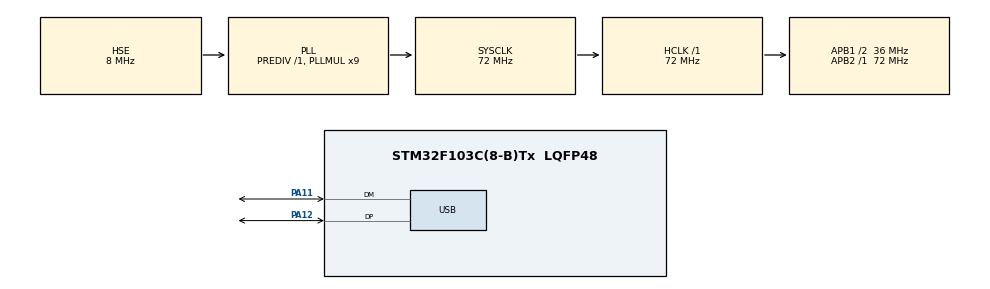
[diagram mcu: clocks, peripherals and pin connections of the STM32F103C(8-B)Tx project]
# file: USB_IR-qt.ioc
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Mcu.Family=STM32F1
Mcu.Name=STM32F103C(8-B)Tx
Mcu.Package=LQFP48
NVIC.PriorityGroup=NVIC_PRIORITYGROUP_4
NVIC.USB_LP_CAN1_RX0_IRQn=true\:0\:0\:false\:false\:true
PA11.Mode=Device
PA11.Signal=USB_DM
PA12.Mode=Device
PA12.Signal=USB_DP
PA13.Mode=Serial_Wire
PA13.Signal=SYS_JTMS-SWDIO
PA14.Mode=Serial_Wire
PA14.Signal=SYS_JTCK-SWCLK
PC14-OSC32_IN.Mode=LSE-External-Oscillator
PC14-OSC32_IN.Signal=RCC_OSC32_IN
PC15-OSC32_OUT.Mode=LSE-External-Oscillator
PC15-OSC32_OUT.Signal=RCC_OSC32_OUT
PD0-OSC_IN.Mode=HSE-External-Oscillator
PD0-OSC_IN.Signal=RCC_OSC_IN
PD1-OSC_OUT.Mode=HSE-External-Oscillator
PD1-OSC_OUT.Signal=RCC_OSC_OUT
ProjectManager.HeapSize=0x200
ProjectManager.StackSize=0x400
ProjectManager.TargetToolchain=Makefile
RCC.AHBFreq_Value=72000000
RCC.APB1CLKDivider=RCC_HCLK_DIV2
RCC.APB1Freq_Value=36000000
RCC.APB1TimFreq_Value=72000000
RCC.APB2Freq_Value=72000000
RCC.APB2TimFreq_Value=72000000
RCC.EnbaleCSS=true
RCC.HCLKFreq_Value=72000000
RCC.PLLMUL=RCC_PLL_MUL9
RCC.SYSCLKFreq_VALUE=72000000
RCC.SYSCLKSource=RCC_SYSCLKSOURCE_PLLCLK
RCC.USBFreq_Value=48000000
RCC.USBPrescaler=RCC_USBCLKSOURCE_PLL_DIV1_5
USB_DEVICE.CLASS_NAME_FS=HID
USB_DEVICE.USBD_SELF_POWERED=0
USB_DEVICE.VirtualMode=Hid
USB_DEVICE.VirtualModeFS=Hid_FS
VP_USB_DEVICE_VS_USB_DEVICE_HID_FS.Mode=HID_FS
board=USB_IR-qt

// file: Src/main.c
/**
  ******************************************************************************
  * File Name          : main.c
  * Description        : Main program body
  ******************************************************************************
  * This notice applies to any and all portions of this file
  * that are not between comment pairs USER CODE BEGIN and
  * USER CODE END. Other portions of this file, whether
  * inserted by the user or by software development tools
  * are owned by their respective copyright owners.
  *
  * Copyright (c) 2017 STMicroelectronics International N.V.
  * All rights reserved.
  *
  * Redistribution and use in source and binary forms, with or without
  * modification, are permitted, provided that the following conditions are met:
  *
  * 1. Redistribution of source code must retain the above copyright notice,
  *    this list of conditions and the following disclaimer.
  * 2. Redistributions in binary form must reproduce the above copyright notice,
  *    this list of conditions and the following disclaimer in the documentation
  *    and/or other materials provided with the distribution.
  * 3. Neither the name of STMicroelectronics nor the names of other
  *    contributors to this software may be used to endorse or promote products
  *    derived from this software without specific written permission.
  * 4. This software, including modifications and/or derivative works of this
  *    software, must execute solely and exclusively on microcontroller or
  *    microprocessor devices manufactured by or for STMicroelectronics.
  * 5. Redistribution and use of this software other than as permitted under
  *    this license is void and will automatically terminate your rights under
  *    this license.
  *
  * THIS SOFTWARE IS PROVIDED BY STMICROELECTRONICS AND CONTRIBUTORS "AS IS"
  * AND ANY EXPRESS, IMPLIED OR STATUTORY WARRANTIES, INCLUDING, BUT NOT
  * LIMITED TO, THE IMPLIED WARRANTIES OF MERCHANTABILITY, FITNESS FOR A
  * PARTICULAR PURPOSE AND NON-INFRINGEMENT OF THIRD PARTY INTELLECTUAL PROPERTY
  * RIGHTS ARE DISCLAIMED TO THE FULLEST EXTENT PERMITTED BY LAW. IN NO EVENT
  * SHALL STMICROELECTRONICS OR CONTRIBUTORS BE LIABLE FOR ANY DIRECT, INDIRECT,
  * INCIDENTAL, SPECIAL, EXEMPLARY, OR CONSEQUENTIAL DAMAGES (INCLUDING, BUT NOT
  * LIMITED TO, PROCUREMENT OF SUBSTITUTE GOODS OR SERVICES; LOSS OF USE, DATA,
  * OR PROFITS; OR BUSINESS INTERRUPTION) HOWEVER CAUSED AND ON ANY THEORY OF
  * LIABILITY, WHETHER IN CONTRACT, STRICT LIABILITY, OR TORT (INCLUDING
  * NEGLIGENCE OR OTHERWISE) ARISING IN ANY WAY OUT OF THE USE OF THIS SOFTWARE,
  * EVEN IF ADVISED OF THE POSSIBILITY OF SUCH DAMAGE.
  *
  ******************************************************************************
  */
#include "main.h"
#include "stm32f1xx_hal.h"
#include "usb_device.h"
#include "usbd_hid.h"

/* USER CODE BEGIN Includes */
#include "diag/Trace.h"
#include "IRremote.h"
#include "IRremoteInt.h"
/* USER CODE END Includes */

/* USER CODE BEGIN PV */
/* Private variables ---------------------------------------------------------*/

// USB media codes
#define USB_HID_SCAN_NEXT 0x01
#define USB_HID_SCAN_PREV 0x02
#define USB_HID_STOP      0x04
#define USB_HID_EJECT     0x08
#define USB_HID_PAUSE     0x10
#define USB_HID_MUTE      0x20
#define USB_HID_VOL_UP    0x40
#define USB_HID_VOL_DEC   0x80

/* USER CODE END PV */

void SystemClock_Config(void);
static void MX_GPIO_Init(void);

/* USER CODE BEGIN PFP */
/* Private function prototypes -----------------------------------------------*/

/* USER CODE END PFP */

int main(void)
{

  /* USER CODE BEGIN 1 */
  // HID Mouse
//  struct mouseHID_t {
//      uint8_t buttons;
//      int8_t x;
//      int8_t y;
//      int8_t wheel;
//  };
//  struct mouseHID_t mouseHID;
//  mouseHID.buttons = 0;
//  mouseHID.x = 10;
//  mouseHID.y = 0;
//  mouseHID.wheel = 0;

  // HID Media
  struct mediaHID_t {
    uint8_t id;
    uint8_t keys;
  };
  struct mediaHID_t mediaHID;
  mediaHID.id = 2;
  mediaHID.keys = 0;
  /* USER CODE END 1 */

  /* MCU Configuration----------------------------------------------------------*/

  /* Reset of all peripherals, Initializes the Flash interface and the Systick. */
  HAL_Init();

  /* Configure the system clock */
  SystemClock_Config();

  /* Initialize all configured peripherals */
  MX_GPIO_Init();
  MX_USB_DEVICE_Init();

  /* USER CODE BEGIN 2 */
  trace_printf("System clock: %u Hz\n", SystemCoreClock);

  unsigned long debug_inc = 0;
  /* USER CODE END 2 */

  /* Infinite loop */
  while (1)
  {

  /* USER CODE BEGIN 3 */
    // Send HID report
//    mouseHID.x = 10;
//    USBD_HID_SendReport(&hUsbDeviceFS, (uint8_t *)&mouseHID, sizeof(struct mouseHID_t));
//    HAL_Delay(1500);
    trace_printf("debug_inc = %d\r\n", debug_inc);
    // Send HID report
    mediaHID.keys = USB_HID_VOL_DEC;
    USBD_HID_SendReport(&hUsbDeviceFS, (uint8_t *)&mediaHID, sizeof(struct mediaHID_t));
    HAL_Delay(30);
    mediaHID.keys = 0;
    USBD_HID_SendReport(&hUsbDeviceFS, (uint8_t *)&mediaHID, sizeof(struct mediaHID_t));
    HAL_Delay(30);

    debug_inc++;
  }
  /* USER CODE END 3 */

}

/** System Clock Configuration
*/
void SystemClock_Config(void)
{

  RCC_OscInitTypeDef RCC_OscInitStruct;
  RCC_ClkInitTypeDef RCC_ClkInitStruct;
  RCC_PeriphCLKInitTypeDef PeriphClkInit;

    /**Initializes the CPU, AHB and APB busses clocks
    */
  RCC_OscInitStruct.OscillatorType = RCC_OSCILLATORTYPE_HSE;
  RCC_OscInitStruct.HSEState = RCC_HSE_ON;
  RCC_OscInitStruct.HSEPredivValue = RCC_HSE_PREDIV_DIV1;
  RCC_OscInitStruct.HSIState = RCC_HSI_ON;
  RCC_OscInitStruct.PLL.PLLState = RCC_PLL_ON;
  RCC_OscInitStruct.PLL.PLLSource = RCC_PLLSOURCE_HSE;
  RCC_OscInitStruct.PLL.PLLMUL = RCC_PLL_MUL9;
  if (HAL_RCC_OscConfig(&RCC_OscInitStruct) != HAL_OK)
  {
    _Error_Handler(__FILE__, __LINE__);
  }

    /**Initializes the CPU, AHB and APB busses clocks
    */
  RCC_ClkInitStruct.ClockType = RCC_CLOCKTYPE_HCLK|RCC_CLOCKTYPE_SYSCLK
                              |RCC_CLOCKTYPE_PCLK1|RCC_CLOCKTYPE_PCLK2;
  RCC_ClkInitStruct.SYSCLKSource = RCC_SYSCLKSOURCE_PLLCLK;
  RCC_ClkInitStruct.AHBCLKDivider = RCC_SYSCLK_DIV1;
  RCC_ClkInitStruct.APB1CLKDivider = RCC_HCLK_DIV2;
  RCC_ClkInitStruct.APB2CLKDivider = RCC_HCLK_DIV1;

  if (HAL_RCC_ClockConfig(&RCC_ClkInitStruct, FLASH_LATENCY_2) != HAL_OK)
  {
    _Error_Handler(__FILE__, __LINE__);
  }

  PeriphClkInit.PeriphClockSelection = RCC_PERIPHCLK_USB;
  PeriphClkInit.UsbClockSelection = RCC_USBCLKSOURCE_PLL_DIV1_5;
  if (HAL_RCCEx_PeriphCLKConfig(&PeriphClkInit) != HAL_OK)
  {
    _Error_Handler(__FILE__, __LINE__);
  }

    /**Enables the Clock Security System
    */
  HAL_RCC_EnableCSS();

    /**Configure the Systick interrupt time
    */
  HAL_SYSTICK_Config(HAL_RCC_GetHCLKFreq()/1000);

    /**Configure the Systick
    */
  HAL_SYSTICK_CLKSourceConfig(SYSTICK_CLKSOURCE_HCLK);

  /* SysTick_IRQn interrupt configuration */
  HAL_NVIC_SetPriority(SysTick_IRQn, 0, 0);
}

/** Configure pins as
        * Analog
        * Input
        * Output
        * EVENT_OUT
        * EXTI
*/
static void MX_GPIO_Init(void)
{

    GPIO_InitTypeDef GPIO_InitStruct;

    /* GPIO Ports Clock Enable */
    __HAL_RCC_GPIOC_CLK_ENABLE();
    __HAL_RCC_GPIOD_CLK_ENABLE();
    __HAL_RCC_GPIOA_CLK_ENABLE();
    __HAL_RCC_GPIOB_CLK_ENABLE();

    /*Configure GPIO pin Output Level */
    HAL_GPIO_WritePin(GPIOA, GNDLED_Pin|BLED_Pin|GLED_Pin|RLED_Pin, GPIO_PIN_RESET);

    /*Configure GPIO pin Output Level */
    HAL_GPIO_WritePin(GPIOB, GNDIR_Pin|VCCIR_Pin, GPIO_PIN_RESET);

    /*Configure GPIO pins : GNDLED_Pin BLED_Pin GLED_Pin RLED_Pin */
    GPIO_InitStruct.Pin = GNDLED_Pin|BLED_Pin|GLED_Pin|RLED_Pin;
    GPIO_InitStruct.Mode = GPIO_MODE_OUTPUT_PP;
    GPIO_InitStruct.Speed = GPIO_SPEED_FREQ_LOW;
    HAL_GPIO_Init(GPIOA, &GPIO_InitStruct);

    /*Configure GPIO pin : IRPIN_Pin */
    GPIO_InitStruct.Pin = IRPIN_Pin;
    GPIO_InitStruct.Mode = GPIO_MODE_INPUT;
    GPIO_InitStruct.Pull = GPIO_NOPULL;
    HAL_GPIO_Init(IRPIN_GPIO_Port, &GPIO_InitStruct);

    /*Configure GPIO pins : GNDIR_Pin VCCIR_Pin */
    GPIO_InitStruct.Pin = GNDIR_Pin|VCCIR_Pin;
    GPIO_InitStruct.Mode = GPIO_MODE_OUTPUT_PP;
    GPIO_InitStruct.Speed = GPIO_SPEED_FREQ_LOW;
    HAL_GPIO_Init(GPIOB, &GPIO_InitStruct);

}

void _Error_Handler(char * file, int line)
{
  while(1)
  {
  }
}

/************************ (C) COPYRIGHT STMicroelectronics *****END OF FILE****/
